VERSION 5.7 ;
  NOWIREEXTENSIONATPIN ON ;
  DIVIDERCHAR "/" ;
  BUSBITCHARS "[]" ;
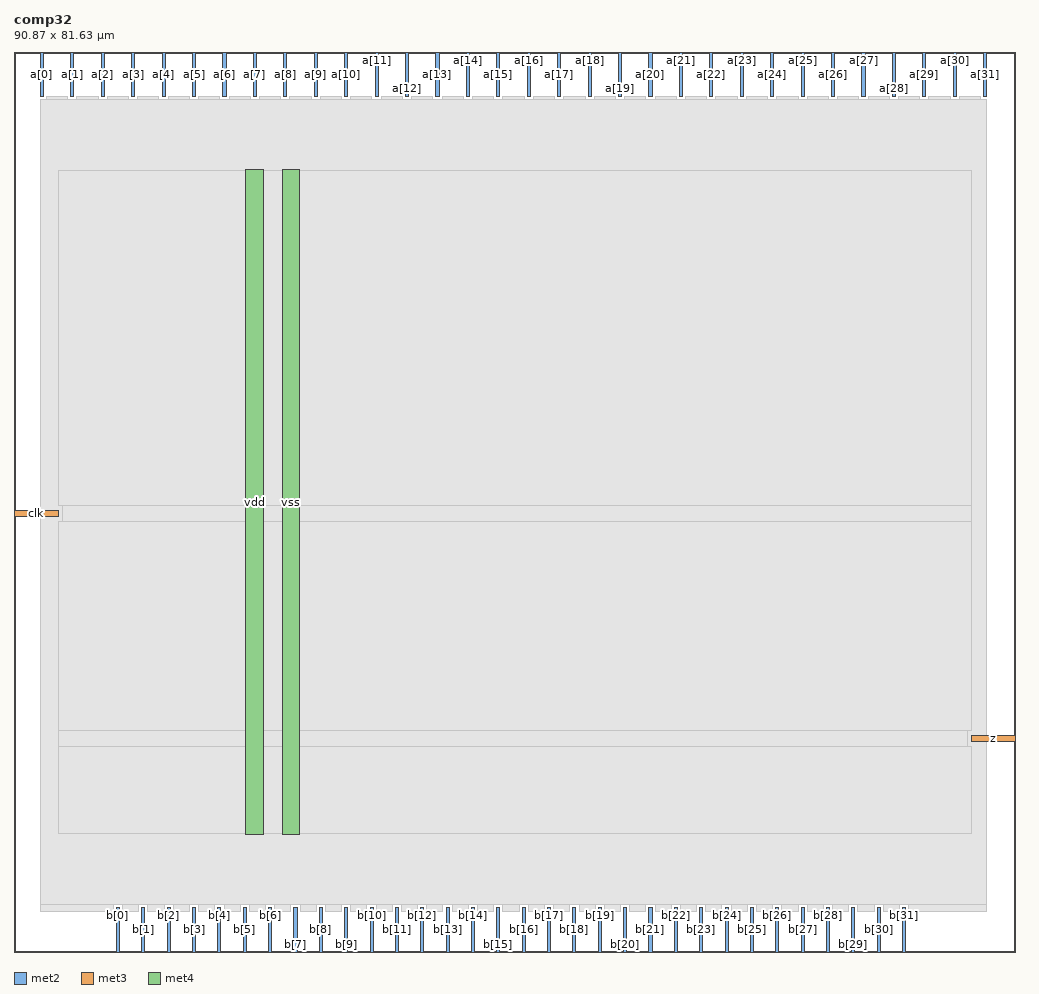
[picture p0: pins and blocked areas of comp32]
MACRO comp32
  CLASS BLOCK ;
  FOREIGN comp32 ;
  ORIGIN 0.000 0.000 ;
  SIZE 90.870 BY 81.630 ;
  PIN a[0]
    DIRECTION INPUT ;
    USE SIGNAL ;
    ANTENNAGATEAREA 0.196500 ;
    PORT
      LAYER met2 ;
        RECT 2.390 77.630 2.670 81.630 ;
    END
  END a[0]
  PIN a[10]
    DIRECTION INPUT ;
    USE SIGNAL ;
    ANTENNAGATEAREA 0.196500 ;
    PORT
      LAYER met2 ;
        RECT 29.990 77.630 30.270 81.630 ;
    END
  END a[10]
  PIN a[11]
    DIRECTION INPUT ;
    USE SIGNAL ;
    ANTENNAGATEAREA 0.196500 ;
    PORT
      LAYER met2 ;
        RECT 32.750 77.630 33.030 81.630 ;
    END
  END a[11]
  PIN a[12]
    DIRECTION INPUT ;
    USE SIGNAL ;
    ANTENNAGATEAREA 0.196500 ;
    PORT
      LAYER met2 ;
        RECT 35.510 77.630 35.790 81.630 ;
    END
  END a[12]
  PIN a[13]
    DIRECTION INPUT ;
    USE SIGNAL ;
    ANTENNAGATEAREA 0.196500 ;
    PORT
      LAYER met2 ;
        RECT 38.270 77.630 38.550 81.630 ;
    END
  END a[13]
  PIN a[14]
    DIRECTION INPUT ;
    USE SIGNAL ;
    ANTENNAGATEAREA 0.196500 ;
    PORT
      LAYER met2 ;
        RECT 41.030 77.630 41.310 81.630 ;
    END
  END a[14]
  PIN a[15]
    DIRECTION INPUT ;
    USE SIGNAL ;
    ANTENNAGATEAREA 0.196500 ;
    PORT
      LAYER met2 ;
        RECT 43.790 77.630 44.070 81.630 ;
    END
  END a[15]
  PIN a[16]
    DIRECTION INPUT ;
    USE SIGNAL ;
    ANTENNAGATEAREA 0.196500 ;
    PORT
      LAYER met2 ;
        RECT 46.550 77.630 46.830 81.630 ;
    END
  END a[16]
  PIN a[17]
    DIRECTION INPUT ;
    USE SIGNAL ;
    ANTENNAGATEAREA 0.196500 ;
    PORT
      LAYER met2 ;
        RECT 49.310 77.630 49.590 81.630 ;
    END
  END a[17]
  PIN a[18]
    DIRECTION INPUT ;
    USE SIGNAL ;
    ANTENNAGATEAREA 0.196500 ;
    PORT
      LAYER met2 ;
        RECT 52.070 77.630 52.350 81.630 ;
    END
  END a[18]
  PIN a[19]
    DIRECTION INPUT ;
    USE SIGNAL ;
    ANTENNAGATEAREA 0.196500 ;
    PORT
      LAYER met2 ;
        RECT 54.830 77.630 55.110 81.630 ;
    END
  END a[19]
  PIN a[1]
    DIRECTION INPUT ;
    USE SIGNAL ;
    ANTENNAGATEAREA 0.196500 ;
    PORT
      LAYER met2 ;
        RECT 5.150 77.630 5.430 81.630 ;
    END
  END a[1]
  PIN a[20]
    DIRECTION INPUT ;
    USE SIGNAL ;
    ANTENNAGATEAREA 0.196500 ;
    PORT
      LAYER met2 ;
        RECT 57.590 77.630 57.870 81.630 ;
    END
  END a[20]
  PIN a[21]
    DIRECTION INPUT ;
    USE SIGNAL ;
    ANTENNAGATEAREA 0.196500 ;
    PORT
      LAYER met2 ;
        RECT 60.350 77.630 60.630 81.630 ;
    END
  END a[21]
  PIN a[22]
    DIRECTION INPUT ;
    USE SIGNAL ;
    ANTENNAGATEAREA 0.196500 ;
    PORT
      LAYER met2 ;
        RECT 63.110 77.630 63.390 81.630 ;
    END
  END a[22]
  PIN a[23]
    DIRECTION INPUT ;
    USE SIGNAL ;
    ANTENNAGATEAREA 0.196500 ;
    PORT
      LAYER met2 ;
        RECT 65.870 77.630 66.150 81.630 ;
    END
  END a[23]
  PIN a[24]
    DIRECTION INPUT ;
    USE SIGNAL ;
    ANTENNAGATEAREA 0.196500 ;
    PORT
      LAYER met2 ;
        RECT 68.630 77.630 68.910 81.630 ;
    END
  END a[24]
  PIN a[25]
    DIRECTION INPUT ;
    USE SIGNAL ;
    ANTENNAGATEAREA 0.196500 ;
    PORT
      LAYER met2 ;
        RECT 71.390 77.630 71.670 81.630 ;
    END
  END a[25]
  PIN a[26]
    DIRECTION INPUT ;
    USE SIGNAL ;
    ANTENNAGATEAREA 0.196500 ;
    PORT
      LAYER met2 ;
        RECT 74.150 77.630 74.430 81.630 ;
    END
  END a[26]
  PIN a[27]
    DIRECTION INPUT ;
    USE SIGNAL ;
    ANTENNAGATEAREA 0.196500 ;
    PORT
      LAYER met2 ;
        RECT 76.910 77.630 77.190 81.630 ;
    END
  END a[27]
  PIN a[28]
    DIRECTION INPUT ;
    USE SIGNAL ;
    ANTENNAGATEAREA 0.196500 ;
    PORT
      LAYER met2 ;
        RECT 79.670 77.630 79.950 81.630 ;
    END
  END a[28]
  PIN a[29]
    DIRECTION INPUT ;
    USE SIGNAL ;
    ANTENNAGATEAREA 0.196500 ;
    PORT
      LAYER met2 ;
        RECT 82.430 77.630 82.710 81.630 ;
    END
  END a[29]
  PIN a[2]
    DIRECTION INPUT ;
    USE SIGNAL ;
    ANTENNAGATEAREA 0.196500 ;
    PORT
      LAYER met2 ;
        RECT 7.910 77.630 8.190 81.630 ;
    END
  END a[2]
  PIN a[30]
    DIRECTION INPUT ;
    USE SIGNAL ;
    ANTENNAGATEAREA 0.196500 ;
    PORT
      LAYER met2 ;
        RECT 85.190 77.630 85.470 81.630 ;
    END
  END a[30]
  PIN a[31]
    DIRECTION INPUT ;
    USE SIGNAL ;
    ANTENNAGATEAREA 0.196500 ;
    PORT
      LAYER met2 ;
        RECT 87.950 77.630 88.230 81.630 ;
    END
  END a[31]
  PIN a[3]
    DIRECTION INPUT ;
    USE SIGNAL ;
    ANTENNAGATEAREA 0.196500 ;
    PORT
      LAYER met2 ;
        RECT 10.670 77.630 10.950 81.630 ;
    END
  END a[3]
  PIN a[4]
    DIRECTION INPUT ;
    USE SIGNAL ;
    ANTENNAGATEAREA 0.196500 ;
    PORT
      LAYER met2 ;
        RECT 13.430 77.630 13.710 81.630 ;
    END
  END a[4]
  PIN a[5]
    DIRECTION INPUT ;
    USE SIGNAL ;
    ANTENNAGATEAREA 0.196500 ;
    PORT
      LAYER met2 ;
        RECT 16.190 77.630 16.470 81.630 ;
    END
  END a[5]
  PIN a[6]
    DIRECTION INPUT ;
    USE SIGNAL ;
    ANTENNAGATEAREA 0.196500 ;
    PORT
      LAYER met2 ;
        RECT 18.950 77.630 19.230 81.630 ;
    END
  END a[6]
  PIN a[7]
    DIRECTION INPUT ;
    USE SIGNAL ;
    ANTENNAGATEAREA 0.196500 ;
    PORT
      LAYER met2 ;
        RECT 21.710 77.630 21.990 81.630 ;
    END
  END a[7]
  PIN a[8]
    DIRECTION INPUT ;
    USE SIGNAL ;
    ANTENNAGATEAREA 0.196500 ;
    PORT
      LAYER met2 ;
        RECT 24.470 77.630 24.750 81.630 ;
    END
  END a[8]
  PIN a[9]
    DIRECTION INPUT ;
    USE SIGNAL ;
    ANTENNAGATEAREA 0.196500 ;
    PORT
      LAYER met2 ;
        RECT 27.230 77.630 27.510 81.630 ;
    END
  END a[9]
  PIN b[0]
    DIRECTION INPUT ;
    USE SIGNAL ;
    ANTENNAGATEAREA 0.196500 ;
    PORT
      LAYER met2 ;
        RECT 9.290 0.000 9.570 4.000 ;
    END
  END b[0]
  PIN b[10]
    DIRECTION INPUT ;
    USE SIGNAL ;
    ANTENNAGATEAREA 0.196500 ;
    PORT
      LAYER met2 ;
        RECT 32.290 0.000 32.570 4.000 ;
    END
  END b[10]
  PIN b[11]
    DIRECTION INPUT ;
    USE SIGNAL ;
    ANTENNAGATEAREA 0.196500 ;
    PORT
      LAYER met2 ;
        RECT 34.590 0.000 34.870 4.000 ;
    END
  END b[11]
  PIN b[12]
    DIRECTION INPUT ;
    USE SIGNAL ;
    ANTENNAGATEAREA 0.196500 ;
    PORT
      LAYER met2 ;
        RECT 36.890 0.000 37.170 4.000 ;
    END
  END b[12]
  PIN b[13]
    DIRECTION INPUT ;
    USE SIGNAL ;
    ANTENNAGATEAREA 0.196500 ;
    PORT
      LAYER met2 ;
        RECT 39.190 0.000 39.470 4.000 ;
    END
  END b[13]
  PIN b[14]
    DIRECTION INPUT ;
    USE SIGNAL ;
    ANTENNAGATEAREA 0.196500 ;
    PORT
      LAYER met2 ;
        RECT 41.490 0.000 41.770 4.000 ;
    END
  END b[14]
  PIN b[15]
    DIRECTION INPUT ;
    USE SIGNAL ;
    ANTENNAGATEAREA 0.196500 ;
    PORT
      LAYER met2 ;
        RECT 43.790 0.000 44.070 4.000 ;
    END
  END b[15]
  PIN b[16]
    DIRECTION INPUT ;
    USE SIGNAL ;
    ANTENNAGATEAREA 0.196500 ;
    PORT
      LAYER met2 ;
        RECT 46.090 0.000 46.370 4.000 ;
    END
  END b[16]
  PIN b[17]
    DIRECTION INPUT ;
    USE SIGNAL ;
    ANTENNAGATEAREA 0.196500 ;
    PORT
      LAYER met2 ;
        RECT 48.390 0.000 48.670 4.000 ;
    END
  END b[17]
  PIN b[18]
    DIRECTION INPUT ;
    USE SIGNAL ;
    ANTENNAGATEAREA 0.196500 ;
    PORT
      LAYER met2 ;
        RECT 50.690 0.000 50.970 4.000 ;
    END
  END b[18]
  PIN b[19]
    DIRECTION INPUT ;
    USE SIGNAL ;
    ANTENNAGATEAREA 0.196500 ;
    PORT
      LAYER met2 ;
        RECT 52.990 0.000 53.270 4.000 ;
    END
  END b[19]
  PIN b[1]
    DIRECTION INPUT ;
    USE SIGNAL ;
    ANTENNAGATEAREA 0.196500 ;
    PORT
      LAYER met2 ;
        RECT 11.590 0.000 11.870 4.000 ;
    END
  END b[1]
  PIN b[20]
    DIRECTION INPUT ;
    USE SIGNAL ;
    ANTENNAGATEAREA 0.196500 ;
    PORT
      LAYER met2 ;
        RECT 55.290 0.000 55.570 4.000 ;
    END
  END b[20]
  PIN b[21]
    DIRECTION INPUT ;
    USE SIGNAL ;
    ANTENNAGATEAREA 0.196500 ;
    PORT
      LAYER met2 ;
        RECT 57.590 0.000 57.870 4.000 ;
    END
  END b[21]
  PIN b[22]
    DIRECTION INPUT ;
    USE SIGNAL ;
    ANTENNAGATEAREA 0.196500 ;
    PORT
      LAYER met2 ;
        RECT 59.890 0.000 60.170 4.000 ;
    END
  END b[22]
  PIN b[23]
    DIRECTION INPUT ;
    USE SIGNAL ;
    ANTENNAGATEAREA 0.196500 ;
    PORT
      LAYER met2 ;
        RECT 62.190 0.000 62.470 4.000 ;
    END
  END b[23]
  PIN b[24]
    DIRECTION INPUT ;
    USE SIGNAL ;
    ANTENNAGATEAREA 0.196500 ;
    PORT
      LAYER met2 ;
        RECT 64.490 0.000 64.770 4.000 ;
    END
  END b[24]
  PIN b[25]
    DIRECTION INPUT ;
    USE SIGNAL ;
    ANTENNAGATEAREA 0.196500 ;
    PORT
      LAYER met2 ;
        RECT 66.790 0.000 67.070 4.000 ;
    END
  END b[25]
  PIN b[26]
    DIRECTION INPUT ;
    USE SIGNAL ;
    ANTENNAGATEAREA 0.196500 ;
    PORT
      LAYER met2 ;
        RECT 69.090 0.000 69.370 4.000 ;
    END
  END b[26]
  PIN b[27]
    DIRECTION INPUT ;
    USE SIGNAL ;
    ANTENNAGATEAREA 0.196500 ;
    PORT
      LAYER met2 ;
        RECT 71.390 0.000 71.670 4.000 ;
    END
  END b[27]
  PIN b[28]
    DIRECTION INPUT ;
    USE SIGNAL ;
    ANTENNAGATEAREA 0.196500 ;
    PORT
      LAYER met2 ;
        RECT 73.690 0.000 73.970 4.000 ;
    END
  END b[28]
  PIN b[29]
    DIRECTION INPUT ;
    USE SIGNAL ;
    ANTENNAGATEAREA 0.196500 ;
    PORT
      LAYER met2 ;
        RECT 75.990 0.000 76.270 4.000 ;
    END
  END b[29]
  PIN b[2]
    DIRECTION INPUT ;
    USE SIGNAL ;
    ANTENNAGATEAREA 0.196500 ;
    PORT
      LAYER met2 ;
        RECT 13.890 0.000 14.170 4.000 ;
    END
  END b[2]
  PIN b[30]
    DIRECTION INPUT ;
    USE SIGNAL ;
    ANTENNAGATEAREA 0.196500 ;
    PORT
      LAYER met2 ;
        RECT 78.290 0.000 78.570 4.000 ;
    END
  END b[30]
  PIN b[31]
    DIRECTION INPUT ;
    USE SIGNAL ;
    ANTENNAGATEAREA 0.196500 ;
    PORT
      LAYER met2 ;
        RECT 80.590 0.000 80.870 4.000 ;
    END
  END b[31]
  PIN b[3]
    DIRECTION INPUT ;
    USE SIGNAL ;
    ANTENNAGATEAREA 0.196500 ;
    PORT
      LAYER met2 ;
        RECT 16.190 0.000 16.470 4.000 ;
    END
  END b[3]
  PIN b[4]
    DIRECTION INPUT ;
    USE SIGNAL ;
    ANTENNAGATEAREA 0.196500 ;
    PORT
      LAYER met2 ;
        RECT 18.490 0.000 18.770 4.000 ;
    END
  END b[4]
  PIN b[5]
    DIRECTION INPUT ;
    USE SIGNAL ;
    ANTENNAGATEAREA 0.196500 ;
    PORT
      LAYER met2 ;
        RECT 20.790 0.000 21.070 4.000 ;
    END
  END b[5]
  PIN b[6]
    DIRECTION INPUT ;
    USE SIGNAL ;
    ANTENNAGATEAREA 0.196500 ;
    PORT
      LAYER met2 ;
        RECT 23.090 0.000 23.370 4.000 ;
    END
  END b[6]
  PIN b[7]
    DIRECTION INPUT ;
    USE SIGNAL ;
    ANTENNAGATEAREA 0.196500 ;
    PORT
      LAYER met2 ;
        RECT 25.390 0.000 25.670 4.000 ;
    END
  END b[7]
  PIN b[8]
    DIRECTION INPUT ;
    USE SIGNAL ;
    ANTENNAGATEAREA 0.196500 ;
    PORT
      LAYER met2 ;
        RECT 27.690 0.000 27.970 4.000 ;
    END
  END b[8]
  PIN b[9]
    DIRECTION INPUT ;
    USE SIGNAL ;
    ANTENNAGATEAREA 0.196500 ;
    PORT
      LAYER met2 ;
        RECT 29.990 0.000 30.270 4.000 ;
    END
  END b[9]
  PIN clk
    DIRECTION INPUT ;
    USE SIGNAL ;
    ANTENNAGATEAREA 0.159000 ;
    ANTENNADIFFAREA 0.434700 ;
    PORT
      LAYER met3 ;
        RECT 0.000 39.480 4.000 40.080 ;
    END
  END clk
  PIN vdd
    DIRECTION INOUT ;
    USE POWER ;
    PORT
      LAYER met4 ;
        RECT 21.040 10.640 22.640 70.960 ;
    END
  END vdd
  PIN vss
    DIRECTION INOUT ;
    USE GROUND ;
    PORT
      LAYER met4 ;
        RECT 24.340 10.640 25.940 70.960 ;
    END
  END vss
  PIN z
    DIRECTION OUTPUT ;
    USE SIGNAL ;
    ANTENNADIFFAREA 0.445500 ;
    PORT
      LAYER met3 ;
        RECT 86.870 19.080 90.870 19.680 ;
    END
  END z
  OBS
      LAYER li1 ;
        RECT 5.520 10.795 85.100 70.805 ;
      LAYER met1 ;
        RECT 2.370 10.640 88.250 70.960 ;
      LAYER met2 ;
        RECT 2.950 77.350 4.870 77.630 ;
        RECT 5.710 77.350 7.630 77.630 ;
        RECT 8.470 77.350 10.390 77.630 ;
        RECT 11.230 77.350 13.150 77.630 ;
        RECT 13.990 77.350 15.910 77.630 ;
        RECT 16.750 77.350 18.670 77.630 ;
        RECT 19.510 77.350 21.430 77.630 ;
        RECT 22.270 77.350 24.190 77.630 ;
        RECT 25.030 77.350 26.950 77.630 ;
        RECT 27.790 77.350 29.710 77.630 ;
        RECT 30.550 77.350 32.470 77.630 ;
        RECT 33.310 77.350 35.230 77.630 ;
        RECT 36.070 77.350 37.990 77.630 ;
        RECT 38.830 77.350 40.750 77.630 ;
        RECT 41.590 77.350 43.510 77.630 ;
        RECT 44.350 77.350 46.270 77.630 ;
        RECT 47.110 77.350 49.030 77.630 ;
        RECT 49.870 77.350 51.790 77.630 ;
        RECT 52.630 77.350 54.550 77.630 ;
        RECT 55.390 77.350 57.310 77.630 ;
        RECT 58.150 77.350 60.070 77.630 ;
        RECT 60.910 77.350 62.830 77.630 ;
        RECT 63.670 77.350 65.590 77.630 ;
        RECT 66.430 77.350 68.350 77.630 ;
        RECT 69.190 77.350 71.110 77.630 ;
        RECT 71.950 77.350 73.870 77.630 ;
        RECT 74.710 77.350 76.630 77.630 ;
        RECT 77.470 77.350 79.390 77.630 ;
        RECT 80.230 77.350 82.150 77.630 ;
        RECT 82.990 77.350 84.910 77.630 ;
        RECT 85.750 77.350 87.670 77.630 ;
        RECT 2.400 4.280 88.220 77.350 ;
        RECT 2.400 3.670 9.010 4.280 ;
        RECT 9.850 3.670 11.310 4.280 ;
        RECT 12.150 3.670 13.610 4.280 ;
        RECT 14.450 3.670 15.910 4.280 ;
        RECT 16.750 3.670 18.210 4.280 ;
        RECT 19.050 3.670 20.510 4.280 ;
        RECT 21.350 3.670 22.810 4.280 ;
        RECT 23.650 3.670 25.110 4.280 ;
        RECT 25.950 3.670 27.410 4.280 ;
        RECT 28.250 3.670 29.710 4.280 ;
        RECT 30.550 3.670 32.010 4.280 ;
        RECT 32.850 3.670 34.310 4.280 ;
        RECT 35.150 3.670 36.610 4.280 ;
        RECT 37.450 3.670 38.910 4.280 ;
        RECT 39.750 3.670 41.210 4.280 ;
        RECT 42.050 3.670 43.510 4.280 ;
        RECT 44.350 3.670 45.810 4.280 ;
        RECT 46.650 3.670 48.110 4.280 ;
        RECT 48.950 3.670 50.410 4.280 ;
        RECT 51.250 3.670 52.710 4.280 ;
        RECT 53.550 3.670 55.010 4.280 ;
        RECT 55.850 3.670 57.310 4.280 ;
        RECT 58.150 3.670 59.610 4.280 ;
        RECT 60.450 3.670 61.910 4.280 ;
        RECT 62.750 3.670 64.210 4.280 ;
        RECT 65.050 3.670 66.510 4.280 ;
        RECT 67.350 3.670 68.810 4.280 ;
        RECT 69.650 3.670 71.110 4.280 ;
        RECT 71.950 3.670 73.410 4.280 ;
        RECT 74.250 3.670 75.710 4.280 ;
        RECT 76.550 3.670 78.010 4.280 ;
        RECT 78.850 3.670 80.310 4.280 ;
        RECT 81.150 3.670 88.220 4.280 ;
      LAYER met3 ;
        RECT 4.000 40.480 86.870 70.885 ;
        RECT 4.400 39.080 86.870 40.480 ;
        RECT 4.000 20.080 86.870 39.080 ;
        RECT 4.000 18.680 86.470 20.080 ;
        RECT 4.000 10.715 86.870 18.680 ;
  END
END comp32
END LIBRARY

